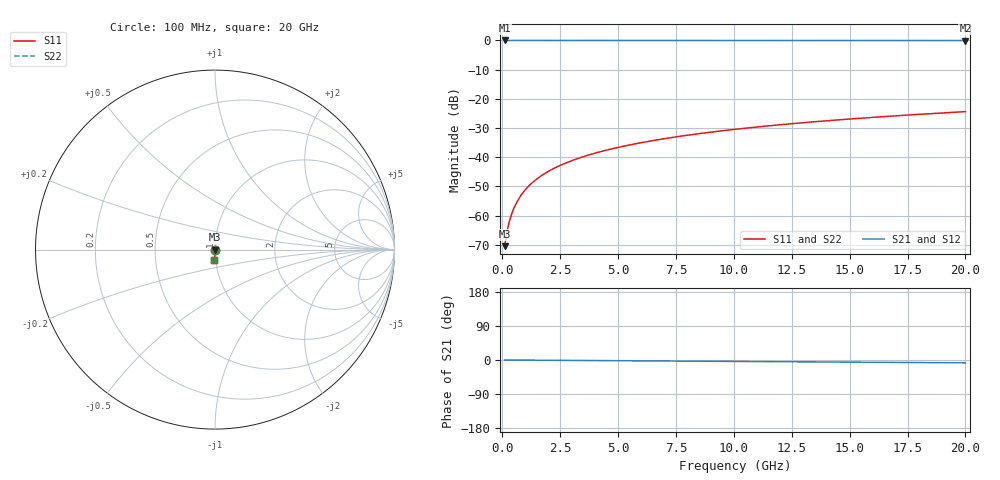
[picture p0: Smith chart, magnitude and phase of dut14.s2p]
! Touchstone file exported from HFSS 2026.1.0
!  File:  C:/ffzhzh/LocalFiles/Ansys_Project_Files/temp_test_TSV_14_1782978282_15332.aedt
!  Generated:  03:46:10 PM Jul  2, 2026
!  Design:  TSV
!  Project:  temp_test_TSV_14_1782978282_15332
! Variables:
!  h_bsmrdl = 2um
!  h_ox = 20um
!  h_rdl = 5um
!  h_sub = 71.34um
!  h_tmrdl = 5um
!  h_tsv = 71.34um
!  h_via = 3um
!  l_bsmrdl = 300um
!  l_sub = 416.26um
!  l_tmrdl = 200um
!  m_sub = 200um
!  pitch = 21.96um
!  r_tsv = 8.13um
!  s_tmrdl = 10um
!  w_bsmrdl = 18um
!  w_sub = 500um
!  w_tmrdl = 12um
!  x_tsv_center1 = 206um
!  x_tsv_center2 = 524um
!  x_tsv_center3 = 736um
!  x_tsv_center4 = 1054um
!  x_tsv_center5 = 1266um
!  x_tsv_center6 = 1584um
# GHz S MA R 50.000000
! Terminal data exported
! Port[1] = TSV1_1_T1
! Port[2] = TSV1_1_T2
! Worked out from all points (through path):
!   200 points, 100 MHz to 20 GHz, reference 50 ohm
!   highest |S21| = 0.00 dB at 100 MHz (marker M1); lowest = 0.0 dB at 20 GHz (marker M2)
!   group delay of S21, straight-line fit = 1.04 ps
!   lowest |S11| = -70.5 dB at 100 MHz (marker M3), VSWR 1.00, Z = 50 - j0.0242 ohm
!   |S11| at or under -10 dB: start of sweep to end of sweep
!   |S22| runs from -70.5 to -24.4 dB; largest |S21 - S12| = 5.1e-15
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0.1  0.0002988 -54.0  0.9998 -0.0  0.9998 -0.0  0.0002988 -54.0
! Gamma 0 0 0 0
! Port Impedance 50 0 50 0
0.2  0.0005276 -68.2  0.9998 -0.1  0.9998 -0.1  0.0005276 -68.2
0.3  0.000781 -73.3  0.9998 -0.1  0.9998 -0.1  0.000781 -73.3
0.4  0.001049 -75.8  0.9997 -0.2  0.9997 -0.2  0.001049 -75.8
0.5  0.001327 -77.5  0.9997 -0.2  0.9997 -0.2  0.001327 -77.5
0.7  0.001902 -79.7  0.9996 -0.3  0.9996 -0.3  0.001902 -79.7
0.8  0.002195 -80.5  0.9996 -0.3  0.9996 -0.3  0.002195 -80.5
1  0.002785 -81.8  0.9996 -0.4  0.9996 -0.4  0.002785 -81.8
1.2  0.003377 -82.9  0.9995 -0.5  0.9995 -0.5  0.003377 -82.9
1.4  0.00397 -83.7  0.9995 -0.5  0.9995 -0.5  0.00397 -83.7
1.7  0.004859 -84.7  0.9995 -0.7  0.9995 -0.7  0.004859 -84.7
2  0.005748 -85.4  0.9994 -0.8  0.9994 -0.8  0.005748 -85.4
2.7  0.007826 -86.6  0.9994 -1.0  0.9994 -1.0  0.007826 -86.6
3.5  0.01021 -87.5  0.9993 -1.3  0.9993 -1.3  0.01021 -87.5
4.2  0.01231 -88.1  0.9992 -1.6  0.9992 -1.6  0.01231 -88.1
5  0.01471 -88.7  0.9991 -1.9  0.9991 -1.9  0.01471 -88.7
6.8  0.02016 -89.8  0.9988 -2.6  0.9988 -2.6  0.02016 -89.8
8.3  0.02472 -90.6  0.9986 -3.1  0.9986 -3.1  0.02472 -90.6
10.1  0.03019 -91.5  0.9983 -3.8  0.9983 -3.8  0.03019 -91.5
13.4  0.04022 -93.1  0.9978 -5.0  0.9978 -5.0  0.04022 -93.1
16.7  0.05025 -94.5  0.9972 -6.3  0.9972 -6.3  0.05025 -94.5
20  0.06027 -95.9  0.9965 -7.5  0.9965 -7.5  0.06027 -95.9
